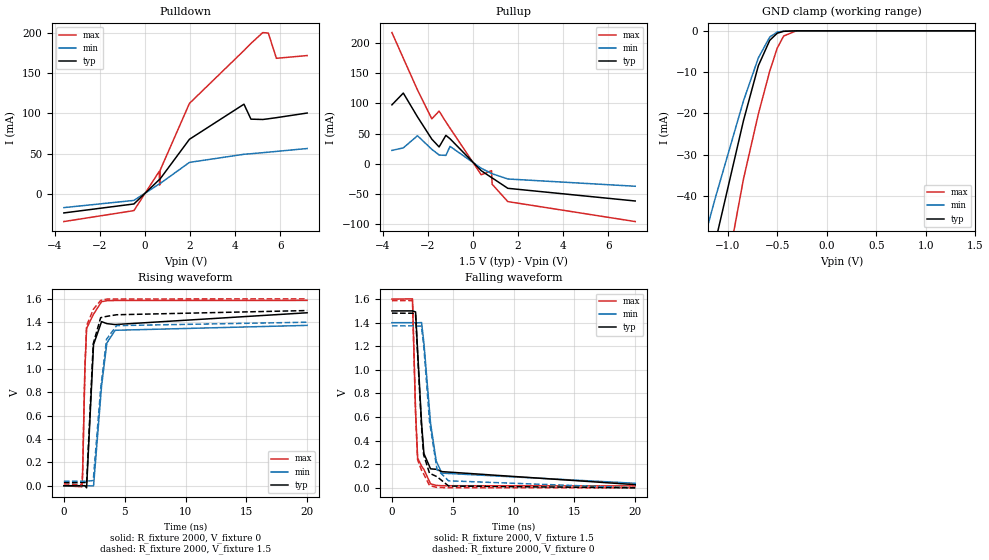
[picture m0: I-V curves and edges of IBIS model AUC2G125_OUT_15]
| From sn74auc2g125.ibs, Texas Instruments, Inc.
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[Model]   AUC2G125_OUT_15
Model_type  3-state
Enable   Active-Low
Vref =   0
Rref =   2000
Cref =   15p
Vmeas =   0.75
| variable   typ   min   max
C_comp   5.27pF   4.71pF   5.53pF
| C_pullup   4.79pF   0.02pF   13.20pF
| C_pulldown   6.36pF   5.33pF   12.83pF
| C_tri-state   5.27pF   4.71pF   5.53pF
[Temperature Range]   40   100   -40
| Ambient temperature   25   85   -40
[Voltage range]   1.5   1.4   1.6
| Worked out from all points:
|   slope of the pulldown table from 0 to 0.225 V, typ, clamps not added: 36.8 ohm
|   slope of the pullup table from 0 to 0.225 V, typ, clamps not added: 29.6 ohm
|   GND clamp passes 1 mA (typ) near -0.53 V on its own axis
|   rising waveform, R_fixture 2000, V_fixture 0: 20-80 % time 401ps typ, 642ps min, 245ps max; typ from 0 V to 1.48 V
|   falling waveform, R_fixture 2000, V_fixture 1.5: 20-80 % time 504ps typ, 797ps min, 274ps max; typ from 1.5 V to 0.027 V
|   rising waveform, R_fixture 2000, V_fixture 1.5: 20-80 % time 396ps typ, 635ps min, 242ps max; typ from 0.027 V to 1.5 V
|   falling waveform, R_fixture 2000, V_fixture 0: 20-80 % time 500ps typ, 784ps min, 272ps max; typ from 1.48 V to 0 V
[GND Clamp]
| AUC2G125_OUT_15
|   Voltage   I(typ)   I(min)   I(max)
-3.6V     -324.8mA   -272.6mA   -395.3mA
-1.51V    -93.07mA   -74.9mA    -123.7mA
-1.465V   -88.13mA   -70.8mA    -117.8mA
-1.33V    -73.37mA   -58.63mA   -100mA
-1.125V   -51.23mA   -40.54mA   -72.92mA
-840mV    -21.74mA   -16.94mA   -35.88mA
-690mV    -8.435mA   -6.553mA   -20.12mA
-575mV    -2.291mA   -1.489mA   -9.733mA
-500mV    -581.2uA   -306.5uA   -4.204mA
-435mV    -119.5uA   -65.92uA   -1.256mA
-310mV    -3.098uA   -2.805uA   -25.01uA
1.5V      384.9pA    7.758nA    386pA
[Pulldown]
| AUC2G125_OUT_15
|   Voltage   I(typ)   I(min)   I(max)
-3.6V     -23.87mA   -17.26mA   -34.61mA
-490mV    -12.71mA   -8.291mA   -20.99mA
630mV     17.4mA     12.02mA    27.68mA
655mV     18.03mA    12.44mA    10.77mA
675mV     18.52mA    12.77mA    29.29mA
1.975V    67.77mA    39mA       112.4mA
4.395V    111.4mA    49.1mA     178.2mA
4.705V    92.8mA     49.77mA    187mA
5.23V     92.39mA    51.08mA    200.5mA
5.475V    93.24mA    51.71mA    199.9mA
5.835V    94.64mA    52.66mA    168.5mA
7.2V      100.4mA    56.27mA    171.9mA
[Pullup]
| AUC2G125_OUT_15
|   Voltage   I(typ)   I(min)   I(max)
-3.6V     97.41mA    22.16mA    216.7mA
-3.095V   116.8mA    26.35mA    174.4mA
-2.465V   77.56mA    46.39mA    122mA
-1.83V    40.8mA     23.97mA    74.26mA
-1.505V   27.88mA    14.58mA    87.05mA
-1.205V   47.01mA    13.93mA    69.21mA
-1.02V    41.38mA    28.81mA    58.8mA
365mV     -11.31mA   -7.286mA   -18.05mA
820mV     -22.63mA   -15.87mA   -11.24mA
850mV     -23.26mA   -16.33mA   -33.73mA
1.545V    -40.41mA   -25mA      -62.34mA
7.2V      -61.35mA   -37.01mA   -95.3mA
[Ramp]
| AUC2G125_OUT_15
| variable   typ   min   max
dV/dt_r   0.90/4.03E-10   0.84/6.50E-10   0.96/2.47E-10
dV/dt_f   0.89/5.06E-10   0.82/8.02E-10   0.95/2.74E-10
R_load = 2000
[Rising Waveform]
| AUC2G125_OUT_15
R_fixture =   2000
C_fixture =   0
L_fixture =   0
V_fixture =   0
V_fixture_min = 0
V_fixture_max = 0
|   Time   V(typ)   V(min)   V(max)
0s        7.607nV    28.63nV    906.6pV
1.49ns    909.4nV    -5.614uV   -8.8mV
1.54ns    38.4uV     -7.465uV   92.79mV
1.73ns    335.6uV    -13.13uV   995.5mV
1.87ns    -18.04mV   79.76uV    1.348V
2.44ns    1.209V     -1.526mV   1.469V
3.1ns     1.405V     855.2mV    1.576V
3.535ns   1.388V     1.222V     1.584V
4.215ns   1.38V      1.331V     1.586V
20ns      1.481V     1.373V     1.587V
[Falling Waveform]
| AUC2G125_OUT_15
R_fixture =   2000
C_fixture =   0
L_fixture =   0
V_fixture =   1.5
V_fixture_min = 1.4
V_fixture_max = 1.6
|   Time   V(typ)   V(min)   V(max)
0s        1.5V       1.4V       1.6V
1.69ns    1.5V       1.4V       1.602V
1.945ns   1.491V     1.4V       644.6mV
2.115ns   1.155V     1.399V     251.8mV
2.435ns   551.1mV    1.401V     184.6mV
2.63ns    290.5mV    1.227V     155.8mV
3.175ns   161.4mV    547.1mV    34.08mV
3.64ns    157.2mV    227.2mV    20.85mV
4.1ns     137.6mV    124.9mV    18.09mV
20ns      27.21mV    38.79mV    16.41mV
[Rising Waveform]
| AUC2G125_OUT_15
R_fixture =   2000
C_fixture =   0
L_fixture =   0
V_fixture =   1.5
V_fixture_min = 1.4
V_fixture_max = 1.6
|   Time   V(typ)   V(min)   V(max)
0s        27.17mV    38.77mV    16.4mV
1.49ns    27.17mV    38.76mV    8.967mV
1.54ns    27.21mV    38.76mV    117.9mV
1.73ns    27.55mV    38.76mV    1.025V
1.87ns    17.97mV    38.85mV    1.37V
2.415ns   1.216V     44.22mV    1.509V
3.025ns   1.439V     830.3mV    1.587V
3.51ns    1.45V      1.255V     1.598V
4.34ns    1.464V     1.371V     1.599V
20ns      1.5V       1.4V       1.6V
[Falling Waveform]
| AUC2G125_OUT_15
R_fixture =   2000
C_fixture =   0
L_fixture =   0
V_fixture =   0
V_fixture_min = 0
V_fixture_max = 0
|   Time   V(typ)   V(min)   V(max)
0s        1.481V     1.373V     1.587V
1.69ns    1.48V      1.373V     1.588V
1.94ns    1.473V     1.372V     641.6mV
2.11ns    1.136V     1.371V     238.2mV
2.42ns    540.4mV    1.372V     152.9mV
2.605ns   281.4mV    1.217V     118.7mV
3.09ns    123.8mV    563.8mV    19.42mV
3.705ns   94.69mV    157mV      3.396mV
4.66ns    15.21mV    59.65mV    555.8uV
20ns      37.61uV    13.37uV    14.79uV
